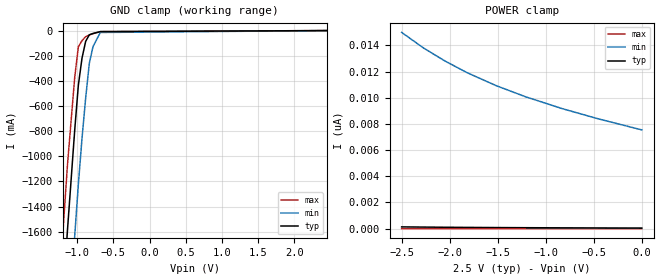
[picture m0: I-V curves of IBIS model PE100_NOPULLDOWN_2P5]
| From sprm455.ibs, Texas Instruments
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|   Model Cell PE100_NOPULLDOWN_2P5
|IDG09_PE100_NOPULLDOWN_2P5
[Model]   PE100_NOPULLDOWN_2P5
Model_type   Input
Polarity   Non-Inverting
Vinl =  0.7V
Vinh =  1.7V
C_comp   1.348p   1.322p   1.399p
[Model Spec]
Vinl   0.7V   0.7V   0.7V
Vinh   1.7V   1.7V   1.7V
[Temperature Range]   25   125   -40
[Voltage Range]   2.5   2.3   2.7
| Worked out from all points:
|   GND clamp passes 1 mA (typ) near -0.54 V on its own axis
[POWER_clamp]
|   voltage   I(typ)   I(min)   I(max)
-2.5V     135.9pA    14.99nA    1.856pA
-2.273V   120.4pA    13.8nA     1.794pA
-2.045V   107pA      12.79nA    1.519pA
-1.818V   96pA       11.91nA    1.421pA
-1.515V   83.69pA    10.92nA    1.004pA
-1.212V   73.32pA    10.08nA    1.021pA
-833.3mV  63.01pA    9.179nA    723.9fA
-454.5mV  54.33pA    8.392nA    595.1fA
0V        45.52pA    7.545nA    439.6fA
[GND_clamp]
|   voltage   I(typ)   I(min)   I(max)
-2.5V     -14.65A    -15.5A     -14.18A
-1.237V   -2.489A    -3.395A    -1.958A
-1.187V   -2.038A    -2.94A     -1.511A
-1.136V   -1.594A    -2.491A    -1.074A
-1.035V   -791.1mA   -1.633A    -371.4mA
-984.8mV  -434.4mA   -1.223A    -129.3mA
-934.3mV  -219.3mA   -857.5mA   -79.98mA
-883.8mV  -85.71mA   -536.6mA   -48.63mA
-833.3mV  -33.72mA   -260.3mA   -35.29mA
-782.8mV  -22.94mA   -128.3mA   -24.88mA
-681.8mV  -8.356mA   -14.97mA   -8.085mA
2.449V    44.71pA    7.814nA    439.6fA
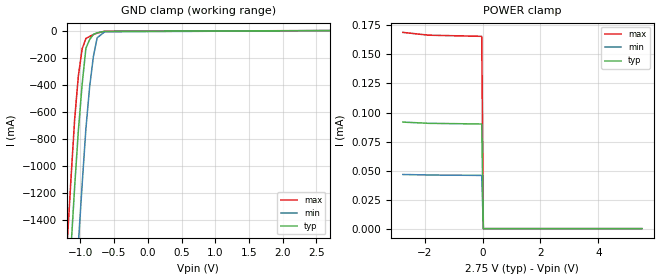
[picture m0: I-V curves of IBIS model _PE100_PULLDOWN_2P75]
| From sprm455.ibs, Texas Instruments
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|   Model Cell _PE100_PULLDOWN_2P75
|IDG09_PE100_PULLDOWN_2P75
[Model]   _PE100_PULLDOWN_2P75
Model_type   Input
Polarity   Non-Inverting
Vinl =  0.7V
Vinh =  1.7V
C_comp   1.4352p   1.3677p   1.4356p
[Model Spec]
Vinl   0.7V   0.7V   0.7V
Vinh   1.7V   1.7V   1.7V
[Temperature Range]   25   125   -40
[Voltage Range]   2.75   2.5   3
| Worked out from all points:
|   GND clamp passes 1 mA (typ) near -0.54 V on its own axis
[POWER_clamp]
|   voltage   I(typ)   I(min)   I(max)
-2.75V    91.76uA    46.64uA    169uA
-1.861V   90.71uA    46.22uA    166.6uA
-27.78mV  90.11uA    45.86uA    165.6uA
27.78mV   0A         0A         0A
5.5V      0A         0A         0A
[GND_clamp]
|   voltage   I(typ)   I(min)   I(max)
-2.75V    -17.11A    -17.95A    -16.64A
-1.194V   -2.105A    -3.008A    -1.577A
-1.139V   -1.621A    -2.516A    -1.105A
-1.083V   -1.151A    -2.031A    -653.7mA
-1.028V   -736.7mA   -1.572A    -333.4mA
-972.2mV  -396.7mA   -1.136A    -134.9mA
-916.7mV  -130.5mA   -725.1mA   -58.19mA
-861.1mV  -66.02mA   -415.2mA   -43.02mA
-805.6mV  -28.04mA   -191.3mA   -29.77mA
-750mV    -16.54mA   -53.31mA   -18.44mA
-638.9mV  -5.317mA   -9.043mA   -4.754mA
2.694V    90.08uA    45.91uA    165.4uA
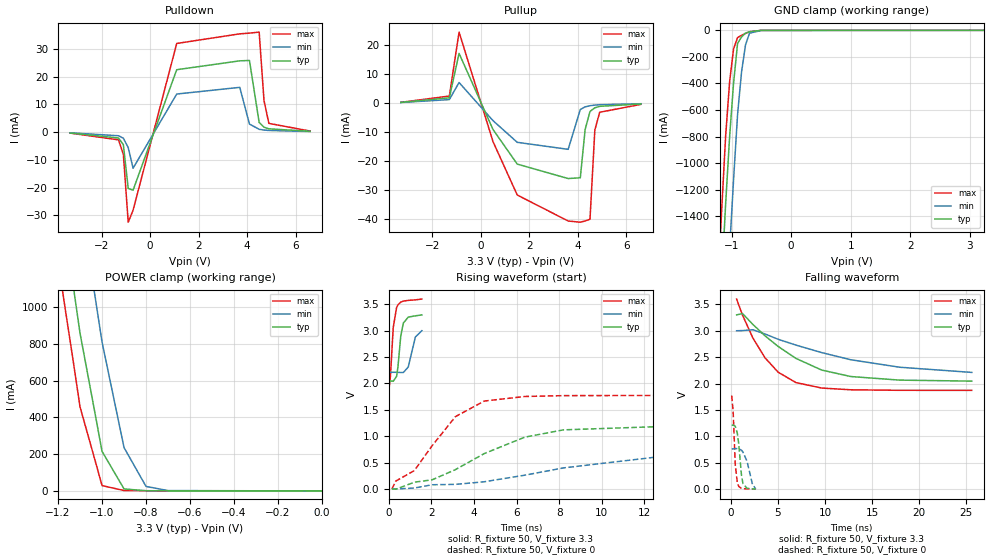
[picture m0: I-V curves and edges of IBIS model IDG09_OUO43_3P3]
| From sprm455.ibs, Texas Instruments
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|   Model Cell IDG09_OUO43_3P3
|IDG09_OUO43_3P3
[Model]   IDG09_OUO43_3P3
Model_type   I/O
Polarity   Non-Inverting
Enable   Active-Low
Vinl =  0.8V
Vinh =  2V
Cref =  15pF
Rref =  100.00M
Vref =  0V
Vmeas =  1.65
C_comp   3.452p   3.205p   3.68p
[Model Spec]
Vinl   0.8V   0.8V   0.8V
Vinh   2V   2V   2V
[Temperature Range]   25   125   -40
[Voltage Range]   3.3   3   3.6
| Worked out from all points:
|   slope of the pulldown table from 0 to 0.495 V, typ, clamps not added: 36.1 ohm
|   slope of the pullup table from 0 to 0.495 V, typ, clamps not added: 54.7 ohm
|   GND clamp passes 1 mA (typ) near -0.53 V on its own axis
|   POWER clamp passes 1 mA (typ) near -0.79 V on its own axis
|   rising waveform, R_fixture 50, V_fixture 3.3: 20-80 % time 196ps typ, 253ps min, 173ps max; typ from 2.05 V to 3.3 V
|   rising waveform, R_fixture 50, V_fixture 0: 20-80 % time 3.76ns typ, 7.36ns min, 2.05ns max; typ from 0 V to 1.21 V
|   falling waveform, R_fixture 50, V_fixture 3.3: 20-80 % time 6.28ns typ, 10.3ns min, 3.68ns max; typ from 3.3 V to 2.05 V
|   falling waveform, R_fixture 50, V_fixture 0: 20-80 % time 374ps typ, 639ps min, 257ps max; typ from 1.21 V to 0 V
[POWER_clamp]
|   voltage   I(typ)   I(min)   I(max)
-3.3V     22.02A     22.67A     21.68A
-1.2V     1.685A     2.433A     1.254A
-1.167V   1.409A     2.149A     988.2mA
-1.133V   1.134A     1.865A     722.7mA
-1.1V     858.3mA    1.581A     457.2mA
-1.033V   429.6mA    1.068A     171.8mA
-1V       215.3mA    810.7mA    29.08mA
-900mV    10.98mA    235.7mA    2.069mA
-800mV    1.038mA    24.36mA    1.11mA
-700mV    431.9uA    1.858mA    537.5uA
0V        64.18pA    9.247nA    692.8fA
[Pulldown]
|   voltage   I(typ)   I(min)   I(max)
-3.3V     -312.6uA   -247.6uA   -339.6uA
-1.3V     -2.112mA   -1.305mA   -2.795mA
-1.1V     -4.535mA   -2.2mA     -8.103mA
-900mV    -20.34mA   -5.594mA   -32.51mA
-700mV    -20.95mA   -13.02mA   -28.19mA
1.1V      22.53mA    13.75mA    32mA
3.7V      25.73mA    16.16mA    35.48mA
4.1V      25.87mA    2.915mA    35.73mA
4.5V      3.469mA    1.015mA    36.11mA
4.7V      1.79mA     755.5uA    11.4mA
4.9V      1.19mA     600.1uA    3.153mA
6.6V      301uA      215.6uA    389.2uA
[Pullup]
|   voltage   I(typ)   I(min)   I(max)
-3.3V     241.9uA    204.6uA    268.7uA
-1.3V     1.834mA    1.218mA    2.447mA
-900mV    17.22mA    7.132mA    24.6mA
500mV     -9.137mA   -6.075mA   -13.34mA
1.5V      -21.13mA   -13.59mA   -31.84mA
3.6V      -26.13mA   -16.01mA   -40.84mA
4.1V      -25.86mA   -2.22mA    -41.25mA
4.3V      -9.125mA   -1.296mA   -40.83mA
4.5V      -2.886mA   -904.1uA   -40.22mA
4.7V      -1.624mA   -691.1uA   -9.333mA
4.9V      -1.119mA   -558.2uA   -3.174mA
6.6V      -300uA     -209.5uA   -435.7uA
[GND_clamp]
|   voltage   I(typ)   I(min)   I(max)
-3.3V     -22.56A    -23.38A    -22.1A
-1.233V   -2.474A    -3.386A    -1.94A
-1.167V   -1.883A    -2.789A    -1.356A
-1.1V     -1.306A    -2.2A      -794.6mA
-1.033V   -798.7mA   -1.644A    -385.6mA
-966.7mV  -396.1mA   -1.122A    -138.9mA
-900mV    -98.32mA   -635.4mA   -54.69mA
-833.3mV  -50.11mA   -314.5mA   -37.73mA
-766.7mV  -20.91mA   -110mA     -23.12mA
-700mV    -10.69mA   -21.68mA   -10.86mA
-500mV    -295.4uA   -931.4uA   -103.3uA
3.233V    61.94pA    521.2nA    577.3fA
[Ramp]
| variable   typ   min   max
dV/dt_f 0.76998409/6.3199678n 0.48475413/10.39617n   1.0620974/3.7068971n
dV/dt_r 0.73057926/3.777467n  0.46273198/7.1677684n  1.0707886/2.0671208n
R_load = 50
[Rising Waveform]
R_fixture = 50
V_fixture = 3.3
V_fixture_min = 3
V_fixture_max = 3.6
|   time   V(typ)   V(min)   V(max)
0s        2.046V     2.211V     1.871V
73.82ps   2.046V     2.212V     2.133V
205.9ps   2.042V     2.212V     3.063V
362.4ps   2.134V     2.211V     3.437V
425ps     2.307V     2.21V      3.489V
558.3ps   2.896V     2.208V     3.542V
681.2ps   3.145V     2.207V     3.561V
910.8ps   3.258V     2.312V     3.575V
1.247ns   3.282V     2.882V     3.585V
1.551ns   3.3V       3V         3.6V
[Rising Waveform]
R_fixture = 50
V_fixture = 0
V_fixture_min = 0
V_fixture_max = 0
|   time   V(typ)   V(min)   V(max)
144.1ps   59.51pV    15.79nV    1.333pV
329.8ps   -4.349mV   150.7uV    150mV
1.2ns     128.1mV    16.91mV    348.4mV
2.036ns   173.4mV    79.35mV    820.6mV
3.132ns   367.2mV    86.6mV     1.372V
4.482ns   670.5mV    136.1mV    1.666V
6.384ns   981.3mV    260.5mV    1.753V
8.2ns     1.12V      398.3mV    1.769V
14.29ns   1.204V     685.2mV    1.773V
18.86ns   1.207V     762.2mV    1.773V
[Falling Waveform]
R_fixture = 50
V_fixture = 3.3
V_fixture_min = 3
V_fixture_max = 3.6
|   time   V(typ)   V(min)   V(max)
601ps     3.3V       3V         3.6V
1.224ns   3.326V     3.003V     3.298V
2.328ns   3.12V      3.019V     2.864V
3.617ns   2.904V     2.939V     2.488V
5.026ns   2.702V     2.838V     2.214V
6.912ns   2.476V     2.728V     2.018V
9.651ns   2.255V     2.586V     1.915V
12.73ns   2.133V     2.451V     1.882V
17.94ns   2.065V     2.309V     1.872V
25.6ns    2.046V     2.211V     1.871V
[Falling Waveform]
R_fixture = 50
V_fixture = 0
V_fixture_min = 0
V_fixture_max = 0
|   time   V(typ)   V(min)   V(max)
78.73ps   1.207V     762.2mV    1.773V
228.8ps   1.215V     762.9mV    1.486V
459.4ps   1.192V     767.3mV    460.9mV
680.9ps   1.056V     770mV      120.3mV
833.4ps   847.4mV    766.8mV    48.77mV
1.121ns   258.8mV    736.5mV    15.74mV
1.276ns   106.9mV    703.1mV    11.16mV
1.708ns   16.15mV    528.5mV    5.072mV
2.268ns   5.771mV    105.9mV    2.174mV
2.631ns   59.51pV    15.79nV    1.333pV
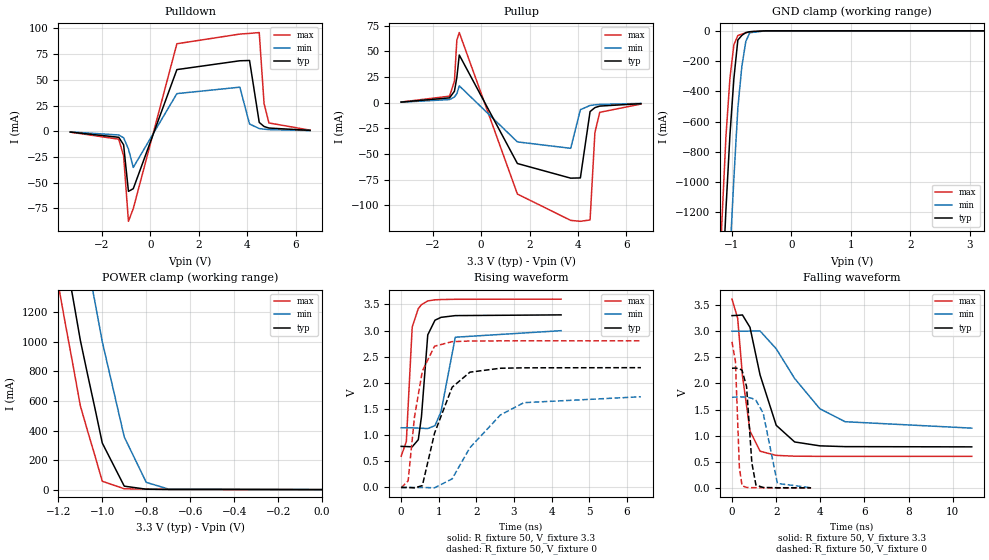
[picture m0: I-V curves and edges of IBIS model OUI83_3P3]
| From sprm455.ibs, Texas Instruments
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|   Model Cell OUI83_3P3
|OUI83_3P3
[Model]   OUI83_3P3
Model_type   3-state
Polarity   Non-Inverting
Enable   Active-Low
Cref =  15.0000pF
Rref =  100.000M
Vref =  0V
Vmeas =  1.65
C_comp   2.0527p   1.8237p   2.5006p
[Temperature Range]   25   125   -40
[Voltage Range]   3.3   3   3.6
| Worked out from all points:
|   slope of the pulldown table from 0 to 0.495 V, typ, clamps not added: 13.6 ohm
|   slope of the pullup table from 0 to 0.495 V, typ, clamps not added: 19.6 ohm
|   GND clamp passes 1 mA (typ) near -0.56 V on its own axis
|   POWER clamp passes 1 mA (typ) near -0.67 V on its own axis
|   rising waveform, R_fixture 50, V_fixture 3.3: 20-80 % time 154ps typ, 249ps min, 117ps max; typ from 0.786 V to 3.3 V
|   rising waveform, R_fixture 50, V_fixture 0: 20-80 % time 594ps typ, 1.18ns min, 320ps max; typ from 0 V to 2.29 V
|   falling waveform, R_fixture 50, V_fixture 3.3: 20-80 % time 950ps typ, 1.94ns min, 464ps max; typ from 3.3 V to 0.785 V
|   falling waveform, R_fixture 50, V_fixture 0: 20-80 % time 221ps typ, 414ps min, 136ps max; typ from 2.29 V to 0.001 V
[POWER_clamp]
|   voltage   I(typ)   I(min)   I(max)
-3.3V     22.22A     22.93A     21.83A
-1.2V     1.856A     2.664A     1.387A
-1.167V   1.575A     2.376A     1.114A
-1.133V   1.294A     2.087A     841.3mA
-1.1V     1.012A     1.799A     568.3mA
-1.067V   780mA      1.533A     397.8mA
-1.033V   547.5mA    1.267A     227.2mA
-1V       315mA      1.001A     56.65mA
-900mV    23.34mA    356.4mA    5.569mA
-800mV    2.724mA    49.13mA    3.088mA
-700mV    1.195mA    4.237mA    1.498mA
0V        34.51pA    5.072nA    381.9fA
[Pulldown]
|   voltage   I(typ)   I(min)   I(max)
-3.3V     -844.2uA   -673.3uA   -913.4uA
-1.3V     -5.909mA   -3.675mA   -7.775mA
-1.1V     -13.23mA   -6.364mA   -23.92mA
-900mV    -58.5mA    -17.26mA   -87.62mA
-700mV    -55.89mA   -35.21mA   -75.22mA
1.1V      59.92mA    36.57mA    85.06mA
3.7V      68.51mA    42.83mA    94.48mA
4.1V      68.77mA    7.012mA    95.13mA
4.5V      8.571mA    2.593mA    95.94mA
4.7V      4.569mA    1.949mA    26.87mA
4.9V      3.077mA    1.558mA    8.02mA
6.6V      795.1uA    568.4uA    1.029mA
[Pullup]
|   voltage   I(typ)   I(min)   I(max)
-3.3V     663.7uA    556.1uA    740.7uA
-1.3V     4.799mA    3.15mA     6.47mA
-1.1V     11.27mA    5.643mA    21.13mA
-1V       24.69mA    8.858mA    61.1mA
-900mV    46.53mA    16.5mA     68.38mA
1.5V      -59.13mA   -38.08mA   -88.86mA
3.7V      -73.39mA   -44.33mA   -114.5mA
4.1V      -73.15mA   -6.679mA   -115.4mA
4.5V      -8.563mA   -2.614mA   -114.1mA
4.7V      -4.706mA   -1.985mA   -29.03mA
4.9V      -3.209mA   -1.596mA   -9.25mA
6.6V      -846.1uA   -591.7uA   -1.226mA
[GND_clamp]
|   voltage   I(typ)   I(min)   I(max)
-3.3V     -22.42A    -23.19A    -21.99A
-1.233V   -2.341A    -3.21A     -1.834A
-1.167V   -1.754A    -2.615A    -1.254A
-1.1V     -1.182A    -2.031A    -698.5mA
-1.033V   -690.4mA   -1.484A    -314.9mA
-966.7mV  -316.7mA   -977.8mA   -92.58mA
-900mV    -61.21mA   -511.7mA   -31.38mA
-833.3mV  -30.3mA    -237.7mA   -21.56mA
-766.7mV  -11.92mA   -71.29mA   -13.15mA
-700mV    -6.061mA   -12.49mA   -6.134mA
-433.3mV  -62.01uA   -221.4uA   -20uA
3.233V    31.96pA    1.414uA    288.7fA
[Ramp]
| variable   typ   min   max
dV/dt_f   1.515799/0.9502244n   1.120018/1.94932n   1.807798/0.4635065n
dV/dt_r   1.383224/0.5945336n   1.050555/1.188655n   1.691312/0.3199966n
R_load = 50
[Rising Waveform]
R_fixture = 50
V_fixture = 3.3
V_fixture_min = 3
V_fixture_max = 3.6
|   time   V(typ)   V(min)   V(max)
0s        785.9mV    1.141V     598.2mV
138ps     782.3mV    1.142V     877.8mV
294ps     777.8mV    1.14V      3.067V
456ps     913mV      1.135V     3.419V
540ps     1.351V     1.132V     3.494V
708ps     2.917V     1.126V     3.566V
900ps     3.197V     1.183V     3.587V
1.062ns   3.252V     1.45V      3.592V
1.44ns    3.285V     2.872V     3.597V
4.254ns   3.299V     2.997V     3.6V
[Rising Waveform]
R_fixture = 50
V_fixture = 0
V_fixture_min = 0
V_fixture_max = 0
|   time   V(typ)   V(min)   V(max)
0s        260.3uV    -52.25uV   -5.827mV
186ps     767.6uV    138.6uV    126.9mV
354ps     -7.084mV   341.5uV    1.344V
564ps     35.55mV    541.1uV    2.226V
888ps     1.037V     -6.231mV   2.7V
1.356ns   1.916V     164.3mV    2.787V
1.83ns    2.204V     760.8mV    2.8V
2.64ns    2.279V     1.386V     2.802V
3.264ns   2.287V     1.621V     2.803V
6.378ns   2.29V      1.734V     2.803V
[Falling Waveform]
R_fixture = 50
V_fixture = 3.3
V_fixture_min = 3
V_fixture_max = 3.6
|   time   V(typ)   V(min)   V(max)
0s        3.299V     3V         3.615V
258ps     3.304V     3V         3.249V
474ps     3.312V     3V         2.151V
816ps     3.074V     3.003V     1.09V
1.272ns   2.163V     3.005V     701.6mV
2.004ns   1.198V     2.664V     622mV
2.838ns   879.3mV    2.095V     606.8mV
3.978ns   804.8mV    1.516V     603.6mV
5.124ns   789.8mV    1.267V     603.3mV
10.86ns   785.3mV    1.144V     603.3mV
[Falling Waveform]
R_fixture = 50
V_fixture = 0
V_fixture_min = 0
V_fixture_max = 0
|   time   V(typ)   V(min)   V(max)
0s        2.291V     1.737V     2.798V
156ps     2.294V     1.738V     2.424V
336ps     2.282V     1.741V     384.6mV
456ps     2.252V     1.742V     41.58mV
660ps     1.942V     1.739V     8.067mV
900ps     478mV      1.716V     4.327mV
1.086ns   52.79mV    1.676V     3.116mV
1.416ns   8.014mV    1.429V     1.825mV
2.058ns   2.729mV    84.12mV    642uV
3.582ns   670.9uV    3.018mV    96.8uV
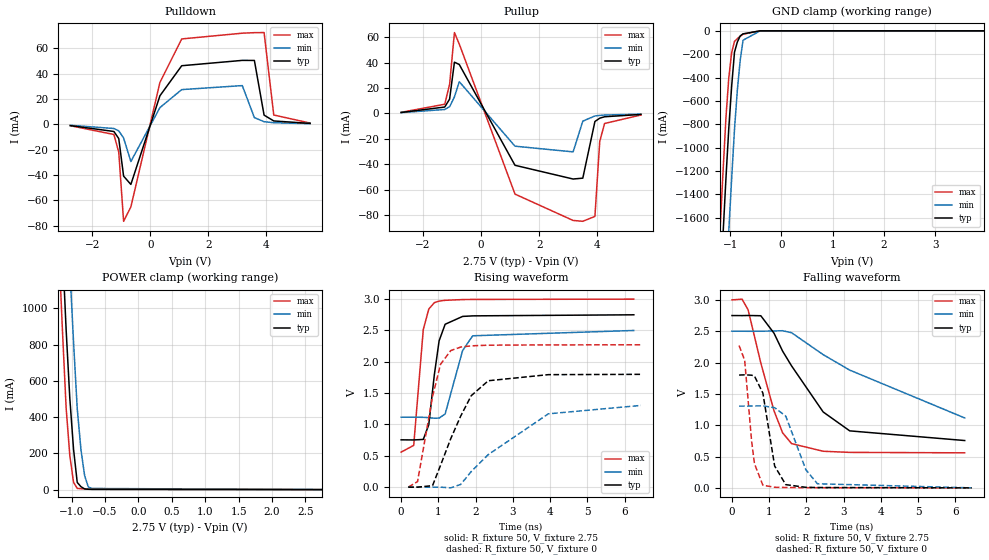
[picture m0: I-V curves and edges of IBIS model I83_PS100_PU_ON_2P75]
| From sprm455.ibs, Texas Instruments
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|   Model Cell I83_PS100_PU_ON_2P75
|IDG09_OUI83_PS100_PU_ON_2P75
[Model]   I83_PS100_PU_ON_2P75
Model_type   I/O
Polarity   Non-Inverting
Enable   Active-Low
Vinl =  0.7V
Vinh =  1.7V
Cref =  15pF
Rref =  100.00M
Vref =  0V
Vmeas =  1.375
C_comp   4.835p   4.751p   5.207p
[Model Spec]
Vinl   0.7V   0.7V   0.7V
Vinh   1.7V   1.7V   1.7V
[Temperature Range]   25   125   -40
[Voltage Range]   2.75   2.5   3
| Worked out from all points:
|   slope of the pulldown table from 0 to 0.412 V, typ, clamps not added: 15.5 ohm
|   slope of the pullup table from 0 to 0.412 V, typ, clamps not added: 22.4 ohm
|   GND clamp passes 1 mA (typ) near -0.51 V on its own axis
|   POWER clamp passes 1 mA (typ) near -0.67 V on its own axis
|   rising waveform, R_fixture 50, V_fixture 2.75: 20-80 % time 246ps typ, 341ps min, 189ps max; typ from 0.755 V to 2.75 V
|   rising waveform, R_fixture 50, V_fixture 0: 20-80 % time 798ps typ, 1.58ns min, 434ps max; typ from 0 V to 1.8 V
|   falling waveform, R_fixture 50, V_fixture 2.75: 20-80 % time 1.32ns typ, 2.55ns min, 663ps max; typ from 2.75 V to 0.755 V
|   falling waveform, R_fixture 50, V_fixture 0: 20-80 % time 289ps typ, 477ps min, 205ps max; typ from 1.8 V to 0 V
| Nom Voltages:
|   VDD=1.1, VDDS=2.75, VSS=0, VSSS=0
| Min Voltages:
|   VDD=1, VDDS=2.5, VSS=0, VSSS=0
| Max Voltages:
|   VDD=1.2, VDDS=3, VSS=0, VSSS=0
[POWER_clamp]
|   voltage   I(typ)   I(min)   I(max)
-2.75V    16.79A     17.52A     16.39A
-1.194V   1.811A     2.617A     1.344A
-1.139V   1.338A     2.134A     883.7mA
-1.083V   881.6mA    1.66A      449.6mA
-1.028V   503.9mA    1.22A      187.7mA
-972.2mV  223.2mA    815.7mA    40.1mA
-916.7mV  39.4mA     445.9mA    6.665mA
-861.1mV  16.07mA    220.1mA    4.789mA
-805.6mV  3.548mA    76.15mA    3.342mA
-750mV    1.836mA    13.94mA    2.326mA
-694.4mV  1.246mA    6.142mA    1.553mA
2.75V     -77.21uA   -51.88uA   -134uA
[Pulldown]
|   voltage   I(typ)   I(min)   I(max)
-2.75V    -951.5uA   -727.1uA   -1.064mA
-1.25V    -5.613mA   -3.253mA   -7.974mA
-1.083V   -11.23mA   -5.133mA   -22mA
-916.7mV  -40.86mA   -10.78mA   -76.55mA
-666.7mV  -47.43mA   -29.33mA   -65.21mA
333.3mV   22.59mA    13.28mA    33.12mA
1.083V    46.33mA    27.47mA    67.49mA
3.167V    50.55mA    30.63mA    72.03mA
3.583V    50.51mA    5.33mA     72.44mA
3.917V    7.298mA    2.134mA    72.52mA
4.25V     2.705mA    1.306mA    7.402mA
5.5V      771.4uA    522.6uA    1.048mA
[Pullup]
|   voltage   I(typ)   I(min)   I(max)
-2.75V    781.9uA    636.2uA    897.4uA
-1.25V    5.061mA    3.14mA     7.247mA
-1.083V   11.26mA    5.325mA    22.87mA
-916.7mV  40.27mA    13.02mA    63.52mA
-750mV    38.45mA    24.96mA    54.5mA
1.167V    -40.69mA   -25.69mA   -63.3mA
3.167V    -51.47mA   -30.16mA   -84mA
3.5V      -50.78mA   -6.037mA   -84.66mA
3.917V    -6.314mA   -1.951mA   -80.81mA
4.083V    -3.692mA   -1.517mA   -21.92mA
4.25V     -2.581mA   -1.238mA   -7.85mA
5.5V      -773uA     -514.5uA   -1.206mA
[GND_clamp]
|   voltage   I(typ)   I(min)   I(max)
-2.75V    -17.23A    -18.11A    -16.74A
-1.194V   -2.218A    -3.158A    -1.668A
-1.139V   -1.732A    -2.663A    -1.193A
-1.083V   -1.257A    -2.175A    -737.7mA
-1.028V   -833.1mA   -1.71A     -401.9mA
-972.2mV  -474.9mA   -1.266A    -186.2mA
-916.7mV  -182.3mA   -842.6mA   -90.54mA
-861.1mV  -95.95mA   -507.3mA   -67.18mA
-805.6mV  -43.86mA   -253.3mA   -46.63mA
-750mV    -26.04mA   -80.68mA   -28.91mA
-416.7mV  -125.1uA   -319.8uA   -143.6uA
5.5V      0A         0A         0A
[Ramp]
| variable   typ   min   max
dV/dt_f  1.2043051/1.32745n   0.83534644/2.5516564n  1.4743397/0.66631327n
dV/dt_r  1.0876539/0.80138031n 0.78881693/1.5828421n  1.3704544/0.43473961n
R_load = 50
[Rising Waveform]
R_fixture = 50
V_fixture = 2.75
V_fixture_min = 2.5
V_fixture_max = 3
|   time   V(typ)   V(min)   V(max)
0s        755.2mV    1.116V     559.1mV
337.6ps   753.3mV    1.117V     666.7mV
594.4ps   761.6mV    1.114V     2.514V
741.8ps   994.9mV    1.109V     2.841V
890.2ps   1.787V     1.1V       2.943V
1.02ns    2.336V     1.102V     2.969V
1.182ns   2.599V     1.168V     2.981V
1.65ns    2.724V     2.179V     2.993V
1.922ns   2.733V     2.415V     2.995V
6.25ns    2.75V      2.5V       3V
[Rising Waveform]
R_fixture = 50
V_fixture = 0
V_fixture_min = 0
V_fixture_max = 0
|   time   V(typ)   V(min)   V(max)
190.5ps   0V         0V         0V
440.1ps   0V         0V         88.54mV
843.2ps   24.37mV    0V         1.445V
1.057ns   347mV      0V         1.959V
1.332ns   773.6mV    -11.13mV   2.179V
1.6ns     1.135V     43.53mV    2.235V
1.883ns   1.46V      249.4mV    2.255V
2.341ns   1.698V     520.2mV    2.265V
3.953ns   1.795V     1.17V      2.27V
6.44ns    1.8V       1.304V     2.271V
[Falling Waveform]
R_fixture = 50
V_fixture = 2.75
V_fixture_min = 2.5
V_fixture_max = 3
|   time   V(typ)   V(min)   V(max)
0s        2.75V      2.5V       3V
270.5ps   2.749V     2.5V       3.012V
433.5ps   2.751V     2.499V     2.841V
774.4ps   2.747V     2.5V       1.993V
1.129ns   2.468V     2.504V     1.229V
1.36ns    2.182V     2.508V     878.5mV
1.6ns     1.947V     2.476V     706.3mV
2.449ns   1.211V     2.126V     584.1mV
3.163ns   909.5mV    1.879V     566.1mV
6.25ns    755.2mV    1.116V     559.1mV
[Falling Waveform]
R_fixture = 50
V_fixture = 0
V_fixture_min = 0
V_fixture_max = 0
|   time   V(typ)   V(min)   V(max)
190.5ps   1.8V       1.304V     2.271V
340.6ps   1.804V     1.304V     2.038V
528.3ps   1.798V     1.307V     740.7mV
604.3ps   1.784V     1.308V     384.5mV
829.7ps   1.513V     1.309V     42.05mV
1.146ns   348.5mV    1.279V     9.496mV
1.444ns   51.35mV    1.145V     5.816mV
1.985ns   8.432mV    288.1mV    3.056mV
2.295ns   5.589mV    65.24mV    2.271mV
6.44ns    0V         0V         0V
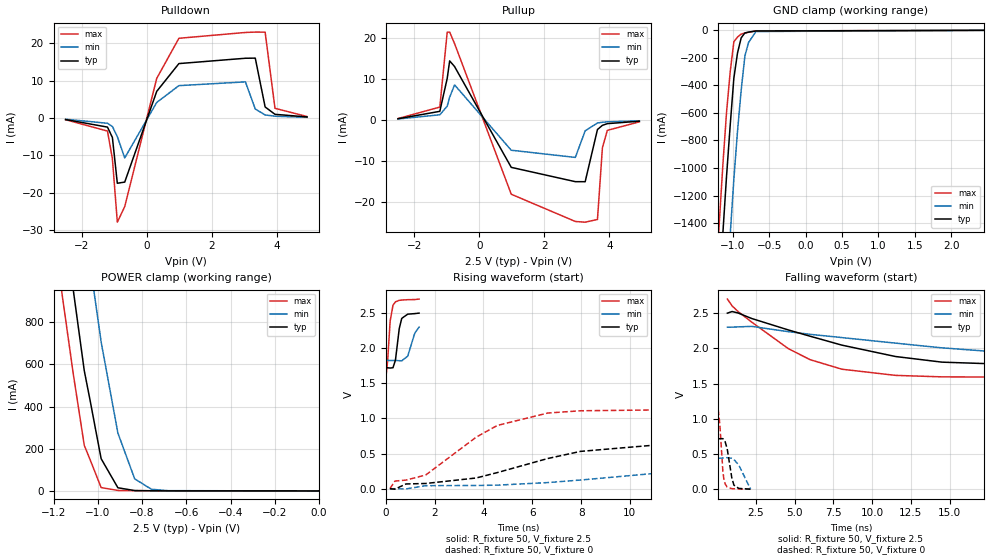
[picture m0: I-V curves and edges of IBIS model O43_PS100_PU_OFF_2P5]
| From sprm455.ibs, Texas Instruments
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|   Model Cell O43_PS100_PU_OFF_2P5
|IDG09_OUO43_PS100_PU_OFF_2P5
[Model]   O43_PS100_PU_OFF_2P5
Model_type   I/O
Polarity   Non-Inverting
Enable   Active-Low
Vinl =  0.7V
Vinh =  1.7V
Cref =  15pF
Rref =  100.00M
Vref =  0V
Vmeas =  1.25
C_comp   1.5511998p   1.5059002p   1.6661999p
[Model Spec]
Vinl   0.7V   0.7V   0.7V
Vinh   1.7V   1.7V   1.7V
[Temperature Range]   25   125   -40
[Voltage Range]   2.5   2.3   2.7
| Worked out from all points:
|   slope of the pulldown table from 0 to 0.375 V, typ, clamps not added: 44.4 ohm
|   slope of the pullup table from 0 to 0.375 V, typ, clamps not added: 67.8 ohm
|   GND clamp passes 1 mA (typ) near -0.57 V on its own axis
|   POWER clamp passes 1 mA (typ) near -0.78 V on its own axis
|   rising waveform, R_fixture 50, V_fixture 2.5: 20-80 % time 166ps typ, 238ps min, 134ps max; typ from 1.72 V to 2.5 V
|   rising waveform, R_fixture 50, V_fixture 0: 20-80 % time 5.66ns typ, 9.6ns min, 2.81ns max; typ from 0 V to 0.711 V
|   falling waveform, R_fixture 50, V_fixture 2.5: 20-80 % time 8.45ns typ, 14.1ns min, 4.75ns max; typ from 2.5 V to 1.72 V
|   falling waveform, R_fixture 50, V_fixture 0: 20-80 % time 312ps typ, 530ps min, 203ps max; typ from 0.711 V to 0 V
[POWER_clamp]
|   voltage   I(typ)   I(min)   I(max)
-2.5V     14.14A     14.81A     13.77A
-1.162V   1.362A     2.103A     937.7mA
-1.111V   954.8mA    1.678A     556.7mA
-1.061V   569.9mA    1.264A     215.7mA
-1.035V   430.9mA    1.078A     149.1mA
-1.01V    291.8mA    892.4mA    82.5mA
-984.8mV  152.8mA    706.5mA    15.88mA
-909.1mV  14.95mA    274.3mA    2.274mA
-833.3mV  1.75mA     57.46mA    1.352mA
-757.6mV  689.5uA    7.871mA    847.4uA
-681.8mV  371.1uA    1.254mA    455.3uA
0V        25.05pA    4.197nA    275.3fA
[Pulldown]
|   voltage   I(typ)   I(min)   I(max)
-2.5V     -396.2uA   -305.7uA   -440.7uA
-1.212V   -2.416mA   -1.384mA   -3.474mA
-1.061V   -5.188mA   -2.255mA   -10.87mA
-909.1mV  -17.44mA   -4.974mA   -27.86mA
-681.8mV  -17.13mA   -10.66mA   -23.68mA
303mV     7.158mA    4.194mA    10.64mA
984.8mV   14.58mA    8.68mA     21.35mA
3.03V     16.01mA    9.688mA    22.91mA
3.333V    16.04mA    2.419mA    23.01mA
3.636V    2.972mA    843.8uA    23mA
3.939V    1.009mA    493.8uA    2.614mA
4.924V    304.5uA    206.1uA    415.7uA
[Pullup]
|   voltage   I(typ)   I(min)   I(max)
-2.5V     313.5uA    255.7uA    361.5uA
-1.212V   2.129mA    1.281mA    3.17mA
-984.8mV  10.18mA    3.39mA     21.48mA
-909.1mV  14.47mA    5.593mA    21.51mA
-757.6mV  13.07mA    8.592mA    18.68mA
984.8mV   -11.57mA   -7.382mA   -18.14mA
2.955V    -15.07mA   -9.137mA   -24.8mA
3.258V    -15.08mA   -2.636mA   -24.98mA
3.636V    -2.316mA   -715uA     -24.31mA
3.788V    -1.293mA   -543uA     -6.804mA
3.939V    -883.6uA   -436.4uA   -2.521mA
4.924V    -281.2uA   -189.2uA   -442.4uA
[GND_clamp]
|   voltage   I(typ)   I(min)   I(max)
-2.5V     -14.52A    -15.32A    -14.07A
-1.187V   -1.916A    -2.778A    -1.414A
-1.136V   -1.475A    -2.331A    -979.5mA
-1.086V   -1.065A    -1.901A    -600.2mA
-1.035V   -689mA     -1.484A    -301.4mA
-984.8mV  -347.4mA   -1.082A    -83.06mA
-934.3mV  -163.7mA   -731.5mA   -48.38mA
-883.8mV  -54.26mA   -433.3mA   -27.25mA
-833.3mV  -19.12mA   -187mA     -19.65mA
-782.8mV  -12.89mA   -87.86mA   -13.84mA
-681.8mV  -4.646mA   -8.6mA     -4.487mA
2.449V    23.98pA    46.38nA    262fA
[Ramp]
| variable   typ   min   max
dV/dt_f 0.48064301/8.5891873n 0.29263296/14.135415n 0.68768907/4.8302366n
dV/dt_r 0.43292076/5.1299078n 0.26884137/9.6299915n 0.68542945/2.8392395n
R_load = 50
[Rising Waveform]
R_fixture = 50
V_fixture = 2.5
V_fixture_min = 2.3
V_fixture_max = 2.7
|   time   V(typ)   V(min)   V(max)
0s        1.722V     1.826V     1.586V
70.8ps    1.722V     1.826V     1.809V
175.9ps   1.718V     1.826V     2.388V
292.7ps   1.723V     1.826V     2.612V
393.1ps   1.832V     1.825V     2.661V
549.7ps   2.282V     1.823V     2.682V
650.9ps   2.425V     1.821V     2.686V
895.1ps   2.485V     1.887V     2.691V
1.185ns   2.493V     2.215V     2.693V
1.36ns    2.5V       2.3V       2.7V
[Rising Waveform]
R_fixture = 50
V_fixture = 0
V_fixture_min = 0
V_fixture_max = 0
|   time   V(typ)   V(min)   V(max)
165.8ps   55pV       16.08nV    1.119pV
369ps     -5.95mV    208.4uV    109.4mV
825.2ps   68.1mV     -2.42mV    123.3mV
1.63ns    74.9mV     43.62mV    195.1mV
3.699ns   153.1mV    46.52mV    734.1mV
4.567ns   230.1mV    51.39mV    901.2mV
6.637ns   430.8mV    87.82mV    1.078V
7.977ns   531.9mV    124.2mV    1.11V
13.38ns   690.6mV    291.6mV    1.13V
22.9ns    710.6mV    439.6mV    1.13V
[Falling Waveform]
R_fixture = 50
V_fixture = 2.5
V_fixture_min = 2.3
V_fixture_max = 2.7
|   time   V(typ)   V(min)   V(max)
653ps     2.5V       2.3V       2.7V
959.7ps   2.523V     2.301V     2.603V
1.346ns   2.502V     2.305V     2.522V
2.222ns   2.424V     2.312V     2.373V
4.593ns   2.261V     2.237V     1.995V
5.999ns   2.172V     2.199V     1.839V
8.041ns   2.046V     2.153V     1.704V
11.51ns   1.884V     2.074V     1.616V
14.51ns   1.804V     2.007V     1.595V
25.65ns   1.722V     1.826V     1.586V
[Falling Waveform]
R_fixture = 50
V_fixture = 0
V_fixture_min = 0
V_fixture_max = 0
|   time   V(typ)   V(min)   V(max)
59.64ps   710.6mV    439.6mV    1.13V
165.1ps   718.4mV    439.6mV    922.3mV
361.1ps   717mV      443mV      254.9mV
424.1ps   705.1mV    444.2mV    145.7mV
506.2ps   675.5mV    445.6mV    75.98mV
641.7ps   572mV      447.2mV    29.61mV
936.4ps   164.6mV    437.8mV    7.429mV
1.072ns   58.28mV    422.6mV    5.325mV
1.387ns   10.85mV    343.6mV    3.207mV
2.151ns   55pV       16.08nV    1.119pV
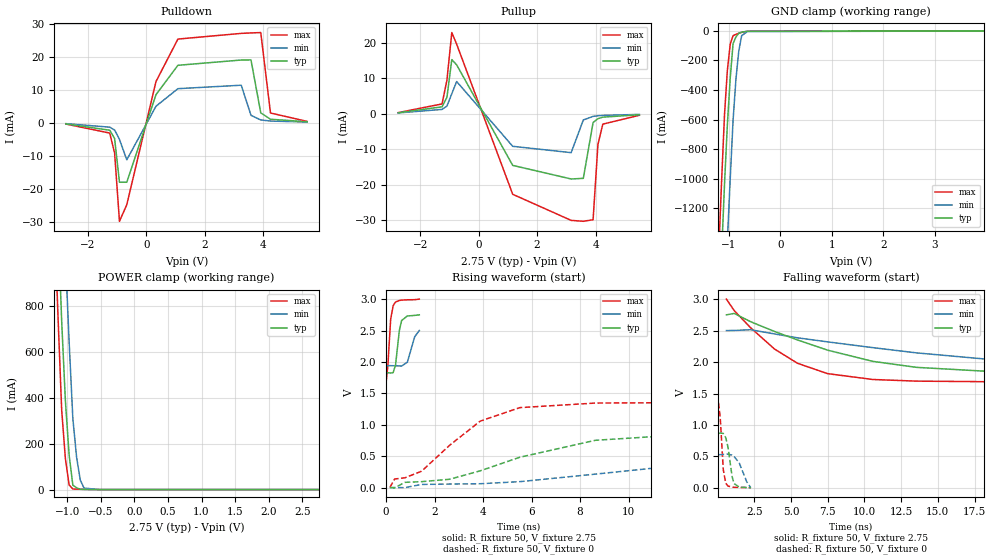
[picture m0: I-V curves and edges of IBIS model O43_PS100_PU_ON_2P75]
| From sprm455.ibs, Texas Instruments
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|   Model Cell O43_PS100_PU_ON_2P75
|IDG09_OUO43_PS100_PU_ON_2P75
[Model]   O43_PS100_PU_ON_2P75
Model_type   I/O
Polarity   Non-Inverting
Enable   Active-Low
Vinl =  0.7V
Vinh =  1.7V
Cref =  15pF
Rref =  100.00M
Vref =  0V
Vmeas =  1.375
C_comp   1.5660002p   1.4978002p   1.7490998p
[Model Spec]
Vinl   0.7V   0.7V   0.7V
Vinh   1.7V   1.7V   1.7V
[Temperature Range]   25   125   -40
[Voltage Range]   2.75   2.5   3
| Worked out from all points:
|   slope of the pulldown table from 0 to 0.412 V, typ, clamps not added: 41 ohm
|   slope of the pullup table from 0 to 0.412 V, typ, clamps not added: 62.6 ohm
|   GND clamp passes 1 mA (typ) near -0.57 V on its own axis
|   POWER clamp passes 1 mA (typ) near -0.77 V on its own axis
|   rising waveform, R_fixture 50, V_fixture 2.75: 20-80 % time 161ps typ, 231ps min, 130ps max; typ from 1.83 V to 2.75 V
|   rising waveform, R_fixture 50, V_fixture 0: 20-80 % time 4.6ns typ, 8.82ns min, 2.5ns max; typ from 0.002 V to 0.865 V
|   falling waveform, R_fixture 50, V_fixture 2.75: 20-80 % time 7.55ns typ, 12.6ns min, 4.28ns max; typ from 2.75 V to 1.83 V
|   falling waveform, R_fixture 50, V_fixture 0: 20-80 % time 320ps typ, 553ps min, 205ps max; typ from 0.865 V to 0.002 V
[POWER_clamp]
|   voltage   I(typ)   I(min)   I(max)
-2.75V    16.6A      17.26A     16.24A
-1.194V   1.641A     2.388A     1.212A
-1.139V   1.177A     1.911A     763.4mA
-1.083V   732.5mA    1.445A     346.7mA
-1.028V   387.7mA    1.022A     135mA
-972.2mV  150mA      643.5mA    20.33mA
-916.7mV  19.37mA    309.1mA    2.593mA
-861.1mV  7.662mA    141.3mA    1.833mA
-805.6mV  1.442mA    40.47mA    1.267mA
-750mV    707.1uA    6.469mA    894.8uA
-527.8mV  101.7uA    163.5uA    119.1uA
2.75V     -77.21uA   -47.95uA   -134uA
[Pulldown]
|   voltage   I(typ)   I(min)   I(max)
-2.75V    -365.9uA   -284.1uA   -404.8uA
-1.25V    -2.275mA   -1.347mA   -3.141mA
-1.083V   -4.808mA   -2.213mA   -9.197mA
-916.7mV  -18.05mA   -5.07mA    -29.89mA
-666.7mV  -18.05mA   -11.25mA   -24.87mA
333.3mV   8.511mA    4.998mA    12.5mA
1.083V    17.41mA    10.32mA    25.36mA
3.25V     19.01mA    11.37mA    27.08mA
3.583V    19.04mA    2.232mA    27.22mA
3.917V    2.992mA    841.3uA    27.33mA
4.25V     1.053mA    505.4uA    2.946mA
5.5V      292.8uA    198.8uA    397.1uA
[Pullup]
|   voltage   I(typ)   I(min)   I(max)
-2.75V    285.7uA    234.9uA    326.2uA
-1.25V    1.953mA    1.223mA    2.77mA
-1.083V   4.622mA    2.158mA    9.493mA
-916.7mV  15.25mA    5.649mA    22.87mA
-750mV    13.77mA    9.085mA    19.58mA
1.167V    -14.54mA   -9.171mA   -22.68mA
3.167V    -18.37mA   -10.95mA   -30.03mA
3.583V    -18.19mA   -1.737mA   -30.29mA
3.917V    -2.45mA    -735.4uA   -29.85mA
4.083V    -1.386mA   -565uA     -8.643mA
4.25V     -954.5uA   -457.6uA   -2.918mA
5.5V      -278.9uA   -186.4uA   -433.5uA
[GND_clamp]
|   voltage   I(typ)   I(min)   I(max)
-2.75V    -16.98A    -17.77A    -16.54A
-1.194V   -1.982A    -2.846A    -1.48A
-1.139V   -1.503A    -2.356A    -1.012A
-1.083V   -1.037A    -1.876A    -566.6mA
-1.028V   -636.6mA   -1.424A    -267.8mA
-972.2mV  -319.5mA   -999.8mA   -89.89mA
-916.7mV  -85.84mA   -603.6mA   -32.81mA
-861.1mV  -41.4mA    -325.9mA   -24.12mA
-805.6mV  -15.87mA   -135.5mA   -16.62mA
-750mV    -9.235mA   -32.49mA   -10.31mA
-638.9mV  -2.997mA   -5.174mA   -2.71mA
5.5V      0A         0A         0A
[Ramp]
| variable   typ   min   max
dV/dt_f 0.56853205/7.6566688n 0.34516444/12.747065n 0.80953373/4.3269163n
dV/dt_r 0.52472307/4.6100892n 0.32179553/8.7558139n 0.81812835/2.5195922n
R_load = 50
[Rising Waveform]
R_fixture = 50
V_fixture = 2.75
V_fixture_min = 2.5
V_fixture_max = 3
|   time   V(typ)   V(min)   V(max)
0s        1.828V     1.94V      1.687V
69.51ps   1.828V     1.941V     1.932V
184.5ps   1.824V     1.941V     2.674V
288.6ps   1.83V      1.94V      2.897V
387.1ps   1.952V     1.94V      2.954V
546.6ps   2.506V     1.937V     2.979V
637.7ps   2.659V     1.935V     2.984V
874.3ps   2.732V     1.996V     2.989V
1.177ns   2.741V     2.402V     2.991V
1.368ns   2.75V      2.5V       3V
[Rising Waveform]
R_fixture = 50
V_fixture = 0
V_fixture_min = 0
V_fixture_max = 0
|   time   V(typ)   V(min)   V(max)
152.6ps   1.513mV    1.199mV    2.044mV
348ps     -3.652mV   1.384mV    137mV
772.1ps   84.23mV    -81.71uV   156.5mV
1.46ns    95.16mV    50.44mV    260.7mV
2.618ns   133.1mV    57.15mV    673.9mV
3.883ns   267.8mV    61.98mV    1.059V
5.515ns   483.5mV    95.11mV    1.273V
8.633ns   753.4mV    214.9mV    1.346V
12.38ns   844.6mV    363.7mV    1.353V
21.42ns   864.6mV    528.5mV    1.353V
[Falling Waveform]
R_fixture = 50
V_fixture = 2.75
V_fixture_min = 2.5
V_fixture_max = 3
|   time   V(typ)   V(min)   V(max)
606.5ps   2.75V      2.5V       3V
1.136ns   2.773V     2.502V     2.818V
2.246ns   2.642V     2.514V     2.547V
3.88ns    2.486V     2.447V     2.207V
5.453ns   2.351V     2.385V     1.98V
7.496ns   2.189V     2.321V     1.816V
10.58ns   2.011V     2.229V     1.723V
13.55ns   1.916V     2.146V     1.697V
18.28ns   1.854V     2.047V     1.688V
25.61ns   1.828V     1.94V      1.687V
[Falling Waveform]
R_fixture = 50
V_fixture = 0
V_fixture_min = 0
V_fixture_max = 0
|   time   V(typ)   V(min)   V(max)
65.84ps   864.6mV    528.5mV    1.353V
183.7ps   873.2mV    528.7mV    1.118V
391.3ps   866.3mV    532.6mV    292.6mV
557.3ps   801.4mV    535.6mV    78.2mV
711.1ps   650.6mV    536.3mV    30.04mV
991.7ps   183.8mV    521.1mV    12.63mV
1.119ns   70.03mV    503.1mV    10.61mV
1.474ns   13.99mV    400mV      7.897mV
1.982ns   6.59mV     101.6mV    5.622mV
2.266ns   1.513mV    1.199mV    2.044mV
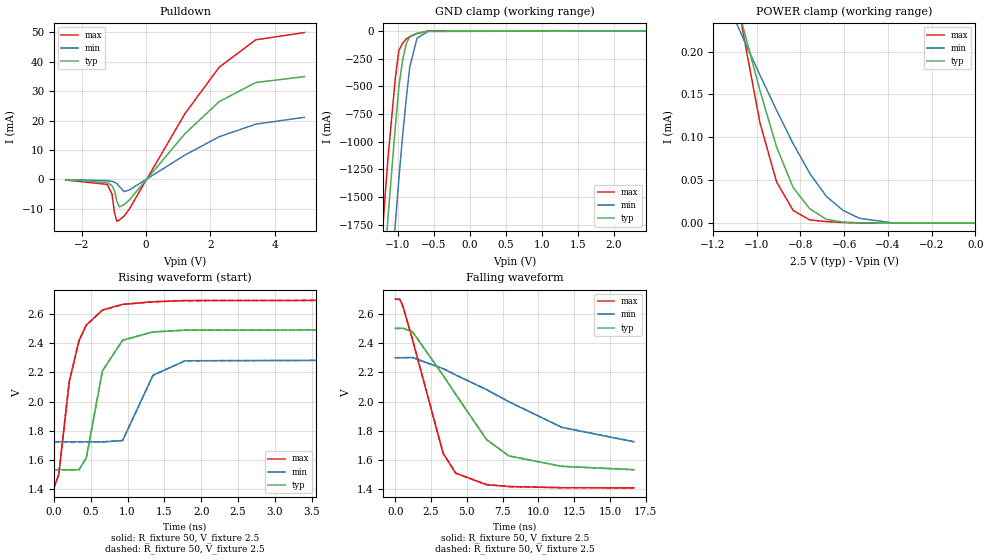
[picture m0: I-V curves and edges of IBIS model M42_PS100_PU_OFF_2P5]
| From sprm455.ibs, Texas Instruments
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|   Model Cell M42_PS100_PU_OFF_2P5
|IDG09_OUM42_PS100_PU_OFF_2P5
[Model]   M42_PS100_PU_OFF_2P5
Model_type   I/O_open_drain
Polarity   Non-Inverting
Enable   Active-Low
Vinl =  0.7V
Vinh =  1.7V
Cref =  15pF
Rref =  100.00M
Vref =  0V
Vmeas =  1.25
C_comp   4.232p   4.190p   4.462p
[Model Spec]
Vinl   0.7V   0.7V   0.7V
Vinh   1.7V   1.7V   1.7V
[Temperature Range]   25   125   -40
[Voltage Range]   2.5   2.3   2.7
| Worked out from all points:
|   slope of the pulldown table from 0 to 0.375 V, typ, clamps not added: 74.6 ohm
|   GND clamp passes 1 mA (typ) near -0.53 V on its own axis
|   POWER clamp passes 1 mA (typ) near -1.78 V on its own axis
|   rising waveform, R_fixture 50, V_fixture 2.5: 20-80 % time 260ps typ, 277ps min, 260ps max; typ from 1.53 V to 2.5 V
|   rising waveform, R_fixture 50, V_fixture 2.5: 20-80 % time 260ps typ, 277ps min, 260ps max; typ from 1.53 V to 2.5 V
|   falling waveform, R_fixture 50, V_fixture 2.5: 20-80 % time 4.11ns typ, 6.99ns min, 2.12ns max; typ from 2.5 V to 1.53 V
|   falling waveform, R_fixture 50, V_fixture 2.5: 20-80 % time 4.11ns typ, 6.99ns min, 2.12ns max; typ from 2.5 V to 1.53 V
| Nom Voltages:
|   VDD=1.1, VDDS=2.5, VSS=0, VSSS=0
| Min Voltages:
|   VDD=1, VDDS=2.3, VSS=0, VSSS=0
| Max Voltages:
|   VDD=1.2, VDDS=2.7, VSS=0, VSSS=0
[POWER_clamp]
|   voltage   I(typ)   I(min)   I(max)
-2.5V     1.799mA    1.079mA    2.669mA
-1.086V   252.9uA    229.2uA    259uA
-1.061V   227.3uA    214.8uA    220.2uA
-984.8mV  154.2uA    172.4uA    116.6uA
-909.1mV  88.74uA    131.4uA    48.03uA
-833.3mV  41.32uA    92.62uA    14.65uA
-757.6mV  16.76uA    57.97uA    3.67uA
-681.8mV  4.381uA    31.21uA    1.697uA
-606.1mV  983.3nA    14.9uA     689.9nA
-530.3mV  264.8nA    5.541uA    165nA
-378.8mV  6.053nA    212nA      1.21nA
0V        70.44pA    11.75nA    746.1fA
[Pulldown]
|   voltage   I(typ)   I(min)   I(max)
-2.5V     -180.8uA   -97.77uA   -227.7uA
-1.212V   -1.061mA   -434.4uA   -1.717mA
-1.061V   -2.159mA   -689.8uA   -4.966mA
-984.8mV  -3.82mA    -950.1uA   -11.34mA
-909.1mV  -7.401mA   -1.439mA   -14.27mA
-833.3mV  -9.346mA   -2.412mA   -13.85mA
-681.8mV  -8.607mA   -4.157mA   -12.46mA
-530.3mV  -7.118mA   -3.662mA   -10.23mA
1.212V    15.56mA    8.277mA    22.39mA
2.273V    26.42mA    14.48mA    38.13mA
3.409V    32.92mA    18.76mA    47.45mA
4.924V    34.93mA    21.1mA     49.91mA
[GND_clamp]
|   voltage   I(typ)   I(min)   I(max)
-2.5V     -14.76A    -15.63A    -14.26A
-1.237V   -2.586A    -3.523A    -2.036A
-1.187V   -2.133A    -3.066A    -1.587A
-1.136V   -1.687A    -2.615A    -1.149A
-1.035V   -874mA     -1.75A     -432.9mA
-984.8mV  -507.8mA   -1.335A    -176.6mA
-934.3mV  -270.9mA   -959.5mA   -114.5mA
-883.8mV  -118.6mA   -623.5mA   -73.58mA
-833.3mV  -50.85mA   -327.1mA   -53.7mA
-732.3mV  -22.21mA   -66.58mA   -24.19mA
-580.8mV  -3.21mA    -5.8mA     -2.153mA
2.449V    69.19pA    12.78nA    735.7fA
[Ramp]
| variable   typ   min   max
dV/dt_f  0.5796769/4.1165754n 0.34452195/6.9930596n 0.77473341/2.1234092n
dV/dt_r 12.927218m/0.10163896n 10.049931m/0.17118576n 14.300118m/67.31188p
R_load = 50
[Rising Waveform]
R_fixture = 50
V_fixture = 2.5
V_fixture_min = 2.3
V_fixture_max = 2.7
|   time   V(typ)   V(min)   V(max)
0s        1.535V     1.726V     1.411V
66.84ps   1.535V     1.726V     1.501V
209.1ps   1.534V     1.726V     2.136V
341.9ps   1.535V     1.726V     2.417V
441.2ps   1.616V     1.726V     2.523V
659.8ps   2.21V      1.725V     2.625V
932.8ps   2.419V     1.734V     2.664V
1.346ns   2.476V     2.18V      2.682V
1.781ns   2.488V     2.279V     2.69V
16.67ns   2.5V       2.3V       2.7V
[Rising Waveform]
R_fixture = 50
V_fixture = 2.5
V_fixture_min = 2.3
V_fixture_max = 2.7
|   time   V(typ)   V(min)   V(max)
0s        1.535V     1.726V     1.411V
66.84ps   1.535V     1.726V     1.501V
209.1ps   1.534V     1.726V     2.136V
341.9ps   1.535V     1.726V     2.417V
441.2ps   1.616V     1.726V     2.523V
659.8ps   2.21V      1.725V     2.625V
932.8ps   2.419V     1.734V     2.664V
1.346ns   2.476V     2.18V      2.682V
1.781ns   2.488V     2.279V     2.69V
16.67ns   2.5V       2.3V       2.7V
[Falling Waveform]
R_fixture = 50
V_fixture = 2.5
V_fixture_min = 2.3
V_fixture_max = 2.7
|   time   V(typ)   V(min)   V(max)
0s        2.5V       2.3V       2.7V
320.3ps   2.5V       2.3V       2.698V
525.9ps   2.501V     2.3V       2.653V
1.206ns   2.476V     2.301V     2.422V
3.341ns   2.179V     2.225V     1.647V
4.221ns   2.049V     2.182V     1.511V
6.372ns   1.741V     2.082V     1.433V
7.936ns   1.629V     1.999V     1.42V
11.64ns   1.558V     1.824V     1.412V
16.67ns   1.535V     1.726V     1.411V
[Falling Waveform]
R_fixture = 50
V_fixture = 2.5
V_fixture_min = 2.3
V_fixture_max = 2.7
|   time   V(typ)   V(min)   V(max)
0s        2.5V       2.3V       2.7V
320.3ps   2.5V       2.3V       2.698V
525.9ps   2.501V     2.3V       2.653V
1.206ns   2.476V     2.301V     2.422V
3.341ns   2.179V     2.225V     1.647V
4.221ns   2.049V     2.182V     1.511V
6.372ns   1.741V     2.082V     1.433V
7.936ns   1.629V     1.999V     1.42V
11.64ns   1.558V     1.824V     1.412V
16.67ns   1.535V     1.726V     1.411V
